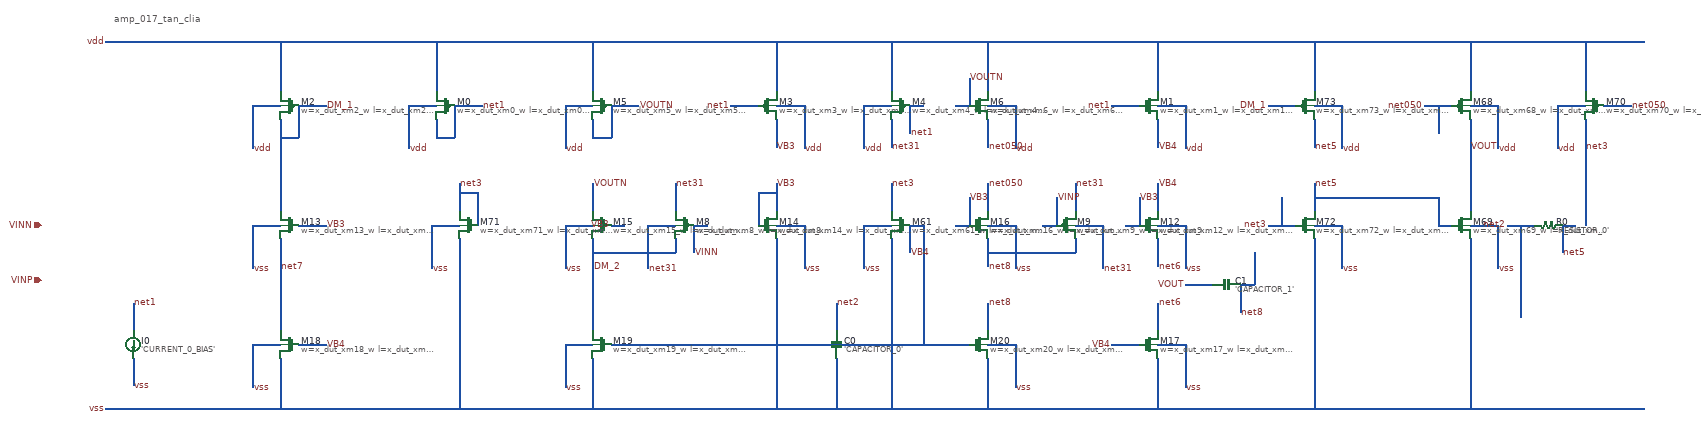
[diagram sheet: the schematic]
v {xschem version=3.4.6 file_version=1.2}
G {}
K {}
V {}
S {}
E {}
T {amp_017_tan_clia} -1570 -200 0 0 0.4 0.4 {}
C {devices/capa_np.sym} 0 520 0 0 {name=C0 value='CAPACITOR_0'}
C {devices/capa_np.sym} 850 390 1 0 {name=C1 value='CAPACITOR_1'}
C {devices/isource_np.sym} -1530 520 0 0 {name=I0 value='CURRENT_0_BIAS'}
C {devices/res_np.sym} 1550 260 1 0 {name=R0 value='RESISTOR_0'}
C {devices/sg13_lv_pmos_np.sym} -850 0 0 1 {name=M0 model=sg13_lv_pmos spiceprefix=X w=x_dut_xm0_w l=x_dut_xm0_l m=x_dut_xm0_m}
C {devices/sg13_lv_pmos_np.sym} 680 0 0 0 {name=M1 model=sg13_lv_pmos spiceprefix=X w=x_dut_xm1_w l=x_dut_xm1_l m=x_dut_xm1_m}
C {devices/sg13_lv_nmos_np.sym} 680 260 0 0 {name=M12 model=sg13_lv_nmos spiceprefix=X w=x_dut_xm12_w l=x_dut_xm12_l m=x_dut_xm12_m}
C {devices/sg13_lv_nmos_np.sym} -1190 260 0 1 {name=M13 model=sg13_lv_nmos spiceprefix=X w=x_dut_xm13_w l=x_dut_xm13_l m=x_dut_xm13_m}
C {devices/sg13_lv_nmos_np.sym} -150 260 0 0 {name=M14 model=sg13_lv_nmos spiceprefix=X w=x_dut_xm14_w l=x_dut_xm14_l m=x_dut_xm14_m}
C {devices/sg13_lv_nmos_np.sym} -510 260 0 1 {name=M15 model=sg13_lv_nmos spiceprefix=X w=x_dut_xm15_w l=x_dut_xm15_l m=x_dut_xm15_m}
C {devices/sg13_lv_nmos_np.sym} 310 260 0 0 {name=M16 model=sg13_lv_nmos spiceprefix=X w=x_dut_xm16_w l=x_dut_xm16_l m=x_dut_xm16_m}
C {devices/sg13_lv_nmos_np.sym} 680 520 0 0 {name=M17 model=sg13_lv_nmos spiceprefix=X w=x_dut_xm17_w l=x_dut_xm17_l m=x_dut_xm17_m}
C {devices/sg13_lv_nmos_np.sym} -1190 520 0 1 {name=M18 model=sg13_lv_nmos spiceprefix=X w=x_dut_xm18_w l=x_dut_xm18_l m=x_dut_xm18_m}
C {devices/sg13_lv_nmos_np.sym} -510 520 0 1 {name=M19 model=sg13_lv_nmos spiceprefix=X w=x_dut_xm19_w l=x_dut_xm19_l m=x_dut_xm19_m}
C {devices/sg13_lv_pmos_np.sym} -1190 0 0 1 {name=M2 model=sg13_lv_pmos spiceprefix=X w=x_dut_xm2_w l=x_dut_xm2_l m=x_dut_xm2_m}
C {devices/sg13_lv_nmos_np.sym} 310 520 0 0 {name=M20 model=sg13_lv_nmos spiceprefix=X w=x_dut_xm20_w l=x_dut_xm20_l m=x_dut_xm20_m}
C {devices/sg13_lv_pmos_np.sym} -150 0 0 0 {name=M3 model=sg13_lv_pmos spiceprefix=X w=x_dut_xm3_w l=x_dut_xm3_l m=x_dut_xm3_m}
C {devices/sg13_lv_pmos_np.sym} 140 0 0 1 {name=M4 model=sg13_lv_pmos spiceprefix=X w=x_dut_xm4_w l=x_dut_xm4_l m=x_dut_xm4_m}
C {devices/sg13_lv_pmos_np.sym} -510 0 0 1 {name=M5 model=sg13_lv_pmos spiceprefix=X w=x_dut_xm5_w l=x_dut_xm5_l m=x_dut_xm5_m}
C {devices/sg13_lv_pmos_np.sym} 310 0 0 0 {name=M6 model=sg13_lv_pmos spiceprefix=X w=x_dut_xm6_w l=x_dut_xm6_l m=x_dut_xm6_m}
C {devices/sg13_lv_nmos_np.sym} 140 260 0 1 {name=M61 model=sg13_lv_nmos spiceprefix=X w=x_dut_xm61_w l=x_dut_xm61_l m=x_dut_xm61_m}
C {devices/sg13_lv_pmos_np.sym} 1360 0 0 0 {name=M68 model=sg13_lv_pmos spiceprefix=X w=x_dut_xm68_w l=x_dut_xm68_l m=x_dut_xm68_m}
C {devices/sg13_lv_nmos_np.sym} 1360 260 0 0 {name=M69 model=sg13_lv_nmos spiceprefix=X w=x_dut_xm69_w l=x_dut_xm69_l m=x_dut_xm69_m}
C {devices/sg13_lv_pmos_np.sym} 1650 0 0 1 {name=M70 model=sg13_lv_pmos spiceprefix=X w=x_dut_xm70_w l=x_dut_xm70_l m=x_dut_xm70_m}
C {devices/sg13_lv_nmos_np.sym} -800 260 0 1 {name=M71 model=sg13_lv_nmos spiceprefix=X w=x_dut_xm71_w l=x_dut_xm71_l m=x_dut_xm71_m}
C {devices/sg13_lv_nmos_np.sym} 1020 260 0 0 {name=M72 model=sg13_lv_nmos spiceprefix=X w=x_dut_xm72_w l=x_dut_xm72_l m=x_dut_xm72_m}
C {devices/sg13_lv_pmos_np.sym} 1020 0 0 0 {name=M73 model=sg13_lv_pmos spiceprefix=X w=x_dut_xm73_w l=x_dut_xm73_l m=x_dut_xm73_m}
C {devices/sg13_lv_pmos_np.sym} -330 260 0 1 {name=M8 model=sg13_lv_pmos spiceprefix=X w=x_dut_xm8_w l=x_dut_xm8_l m=x_dut_xm8_m}
C {devices/sg13_lv_pmos_np.sym} 500 260 0 0 {name=M9 model=sg13_lv_pmos spiceprefix=X w=x_dut_xm9_w l=x_dut_xm9_l m=x_dut_xm9_m}
N -1530 430 -1530 490 {}
N -1530 550 -1530 610 {}
N -1270 0 -1270 94 {}
N -1270 260 -1270 354 {}
N -1270 520 -1270 614 {}
N -1210 -140 -1210 -30 {}
N -1210 30 -1210 230 {}
N -1210 290 -1210 490 {}
N -1210 550 -1210 660 {}
N -1170 0 -1170 70 {}
N -930 0 -930 94 {}
N -880 260 -880 354 {}
N -870 -140 -870 -30 {}
N -870 30 -870 70 {}
N -830 0 -830 70 {}
N -820 170 -820 230 {}
N -820 290 -820 660 {}
N -780 190 -780 260 {}
N -590 0 -590 94 {}
N -590 260 -590 354 {}
N -590 520 -590 614 {}
N -530 -140 -530 -30 {}
N -530 30 -530 70 {}
N -530 170 -530 230 {}
N -530 290 -530 490 {}
N -530 550 -530 660 {}
N -490 0 -490 70 {}
N -410 260 -410 354 {}
N -350 170 -350 230 {}
N -350 290 -350 320 {}
N -310 260 -310 320 {}
N -170 190 -170 260 {}
N -130 -140 -130 -30 {}
N -130 30 -130 90 {}
N -130 170 -130 230 {}
N -130 290 -130 660 {}
N -70 0 -70 94 {}
N -70 260 -70 354 {}
N 0 430 0 490 {}
N 0 550 0 660 {}
N 60 0 60 94 {}
N 60 260 60 354 {}
N 120 -140 120 -30 {}
N 120 30 120 90 {}
N 120 170 120 230 {}
N 120 290 120 660 {}
N 160 0 160 60 {}
N 160 260 160 320 {}
N 190 260 190 520 {}
N 290 -60 290 0 {}
N 290 200 290 260 {}
N 330 -140 330 -30 {}
N 330 30 330 90 {}
N 330 170 330 230 {}
N 330 290 330 350 {}
N 330 430 330 490 {}
N 330 550 330 660 {}
N 390 0 390 94 {}
N 390 260 390 354 {}
N 390 520 390 614 {}
N 480 200 480 260 {}
N 520 170 520 230 {}
N 520 290 520 320 {}
N 580 260 580 354 {}
N 660 200 660 260 {}
N 700 -140 700 -30 {}
N 700 30 700 90 {}
N 700 170 700 230 {}
N 700 290 700 350 {}
N 700 430 700 490 {}
N 700 550 700 660 {}
N 760 0 760 94 {}
N 760 260 760 354 {}
N 760 520 760 614 {}
N 880 390 880 450 {}
N 910 320 910 390 {}
N 970 200 970 260 {}
N 1040 -140 1040 -30 {}
N 1040 30 1040 90 {}
N 1040 170 1040 230 {}
N 1040 290 1040 660 {}
N 1100 0 1100 94 {}
N 1100 260 1100 354 {}
N 1310 0 1310 60 {}
N 1310 200 1310 260 {}
N 1380 -140 1380 -30 {}
N 1380 30 1380 230 {}
N 1380 290 1380 660 {}
N 1440 0 1440 94 {}
N 1440 260 1440 354 {}
N 1490 260 1490 460 {}
N 1570 0 1570 94 {}
N 1580 260 1580 320 {}
N 1630 -140 1630 -30 {}
N 1630 30 1630 260 {}
N -1590 -140 1760 -140 {}
N -1270 0 -1210 0 {}
N -1170 0 -1110 0 {}
N -930 0 -870 0 {}
N -830 0 -770 0 {}
N -590 0 -530 0 {}
N -490 0 -430 0 {}
N -230 0 -170 0 {}
N -130 0 -70 0 {}
N 60 0 120 0 {}
N 160 0 190 0 {}
N 260 0 290 0 {}
N 330 0 390 0 {}
N 600 0 660 0 {}
N 700 0 760 0 {}
N 940 0 1000 0 {}
N 1040 0 1100 0 {}
N 1280 0 1340 0 {}
N 1380 0 1440 0 {}
N 1570 0 1630 0 {}
N 1670 0 1730 0 {}
N -1210 70 -1170 70 {}
N -870 70 -830 70 {}
N -530 70 -490 70 {}
N -820 190 -780 190 {}
N -170 190 -130 190 {}
N 1040 200 1310 200 {}
N -1270 260 -1210 260 {}
N -1170 260 -1110 260 {}
N -880 260 -820 260 {}
N -590 260 -530 260 {}
N -490 260 -460 260 {}
N -410 260 -350 260 {}
N -310 260 -280 260 {}
N -130 260 -70 260 {}
N 60 260 120 260 {}
N 160 260 190 260 {}
N 260 260 290 260 {}
N 330 260 390 260 {}
N 450 260 480 260 {}
N 520 260 580 260 {}
N 630 260 660 260 {}
N 700 260 760 260 {}
N 940 260 1000 260 {}
N 1040 260 1100 260 {}
N 1310 260 1340 260 {}
N 1380 260 1440 260 {}
N 1460 260 1520 260 {}
N 1580 260 1610 260 {}
N -530 320 -350 320 {}
N 330 320 520 320 {}
N 760 390 820 390 {}
N 880 390 910 390 {}
N -1270 520 -1210 520 {}
N -1170 520 -1110 520 {}
N -590 520 -530 520 {}
N -490 520 290 520 {}
N 330 520 390 520 {}
N 600 520 660 520 {}
N 700 520 760 520 {}
N -1590 660 1760 660 {}
C {devices/lab_wire.sym} -1590 -140 0 0 {name=l0 lab=vdd}
C {devices/lab_wire.sym} -1590 660 0 0 {name=l1 lab=vss}
C {devices/lab_wire.sym} -1110 0 0 1 {name=l2 lab=DM_1}
C {devices/lab_wire.sym} 940 0 0 0 {name=l3 lab=DM_1}
C {devices/lab_wire.sym} -530 350 2 0 {name=l4 lab=DM_2}
C {devices/lab_wire.sym} -1110 260 0 1 {name=l5 lab=VB3}
C {devices/lab_wire.sym} -490 260 0 0 {name=l6 lab=VB3}
C {devices/lab_wire.sym} -130 170 0 1 {name=l7 lab=VB3}
C {devices/lab_wire.sym} -130 90 2 0 {name=l8 lab=VB3}
C {devices/lab_wire.sym} 290 200 0 1 {name=l9 lab=VB3}
C {devices/lab_wire.sym} 660 200 0 1 {name=l10 lab=VB3}
C {devices/lab_wire.sym} -1110 520 0 1 {name=l11 lab=VB4}
C {devices/lab_wire.sym} 160 320 2 0 {name=l12 lab=VB4}
C {devices/lab_wire.sym} 600 520 0 0 {name=l13 lab=VB4}
C {devices/lab_wire.sym} 700 90 2 0 {name=l14 lab=VB4}
C {devices/lab_wire.sym} 700 170 0 1 {name=l15 lab=VB4}
C {devices/lab_wire.sym} -310 320 2 0 {name=l16 lab=VINN}
C {devices/lab_wire.sym} 480 200 0 1 {name=l17 lab=VINP}
C {devices/lab_wire.sym} 760 390 0 0 {name=l18 lab=VOUT}
C {devices/lab_wire.sym} 1380 90 2 0 {name=l19 lab=VOUT}
C {devices/lab_wire.sym} -430 0 0 1 {name=l20 lab=VOUTN}
C {devices/lab_wire.sym} -530 170 0 1 {name=l21 lab=VOUTN}
C {devices/lab_wire.sym} 290 -60 0 1 {name=l22 lab=VOUTN}
C {devices/lab_wire.sym} 330 90 2 0 {name=l23 lab=net050}
C {devices/lab_wire.sym} 330 170 0 1 {name=l24 lab=net050}
C {devices/lab_wire.sym} 1280 0 0 0 {name=l25 lab=net050}
C {devices/lab_wire.sym} 1730 0 0 1 {name=l26 lab=net050}
C {devices/lab_wire.sym} -770 0 0 1 {name=l27 lab=net1}
C {devices/lab_wire.sym} -230 0 0 0 {name=l28 lab=net1}
C {devices/lab_wire.sym} 160 60 2 0 {name=l29 lab=net1}
C {devices/lab_wire.sym} 600 0 0 0 {name=l30 lab=net1}
C {devices/lab_wire.sym} 0 430 0 1 {name=l31 lab=net2}
C {devices/lab_wire.sym} 1460 260 0 0 {name=l32 lab=net2}
C {devices/lab_wire.sym} -820 170 0 1 {name=l33 lab=net3}
C {devices/lab_wire.sym} 120 170 0 1 {name=l34 lab=net3}
C {devices/lab_wire.sym} 940 260 0 0 {name=l35 lab=net3}
C {devices/lab_wire.sym} 1630 90 2 0 {name=l36 lab=net3}
C {devices/lab_wire.sym} -350 170 0 1 {name=l37 lab=net31}
C {devices/lab_wire.sym} 120 90 2 0 {name=l38 lab=net31}
C {devices/lab_wire.sym} 520 170 0 1 {name=l39 lab=net31}
C {devices/lab_wire.sym} 1040 90 2 0 {name=l40 lab=net5}
C {devices/lab_wire.sym} 1040 170 0 1 {name=l41 lab=net5}
C {devices/lab_wire.sym} 1580 320 2 0 {name=l42 lab=net5}
C {devices/lab_wire.sym} 700 350 2 0 {name=l43 lab=net6}
C {devices/lab_wire.sym} 700 430 0 1 {name=l44 lab=net6}
C {devices/lab_wire.sym} -1210 350 2 0 {name=l45 lab=net7}
C {devices/lab_wire.sym} 330 350 2 0 {name=l46 lab=net8}
C {devices/lab_wire.sym} 330 430 0 1 {name=l47 lab=net8}
C {devices/lab_wire.sym} 880 450 2 0 {name=l48 lab=net8}
C {devices/lab_wire.sym} -410 354 2 0 {name=l49 lab=net31}
C {devices/lab_wire.sym} 580 354 2 0 {name=l50 lab=net31}
C {devices/lab_wire.sym} -930 94 2 0 {name=l51 lab=vdd}
C {devices/lab_wire.sym} 760 94 2 0 {name=l52 lab=vdd}
C {devices/lab_wire.sym} -1270 94 2 0 {name=l53 lab=vdd}
C {devices/lab_wire.sym} -70 94 2 0 {name=l54 lab=vdd}
C {devices/lab_wire.sym} 60 94 2 0 {name=l55 lab=vdd}
C {devices/lab_wire.sym} -590 94 2 0 {name=l56 lab=vdd}
C {devices/lab_wire.sym} 390 94 2 0 {name=l57 lab=vdd}
C {devices/lab_wire.sym} 1440 94 2 0 {name=l58 lab=vdd}
C {devices/lab_wire.sym} 1570 94 2 0 {name=l59 lab=vdd}
C {devices/lab_wire.sym} 1100 94 2 0 {name=l60 lab=vdd}
C {devices/lab_wire.sym} 760 354 2 0 {name=l61 lab=vss}
C {devices/lab_wire.sym} -1270 354 2 0 {name=l62 lab=vss}
C {devices/lab_wire.sym} -70 354 2 0 {name=l63 lab=vss}
C {devices/lab_wire.sym} -590 354 2 0 {name=l64 lab=vss}
C {devices/lab_wire.sym} 390 354 2 0 {name=l65 lab=vss}
C {devices/lab_wire.sym} 760 614 2 0 {name=l66 lab=vss}
C {devices/lab_wire.sym} -1270 614 2 0 {name=l67 lab=vss}
C {devices/lab_wire.sym} -590 614 2 0 {name=l68 lab=vss}
C {devices/lab_wire.sym} 390 614 2 0 {name=l69 lab=vss}
C {devices/lab_wire.sym} 60 354 2 0 {name=l70 lab=vss}
C {devices/lab_wire.sym} 1440 354 2 0 {name=l71 lab=vss}
C {devices/lab_wire.sym} -880 354 2 0 {name=l72 lab=vss}
C {devices/lab_wire.sym} 1100 354 2 0 {name=l73 lab=vss}
C {devices/lab_wire.sym} -1530 610 2 0 {name=l74 lab=vss}
C {devices/lab_wire.sym} -1530 430 0 1 {name=l75 lab=net1}
C {devices/ipin.sym} -1730 260 0 0 {name=p0 lab=VINN}
C {devices/ipin.sym} -1730 380 0 0 {name=p1 lab=VINP}
